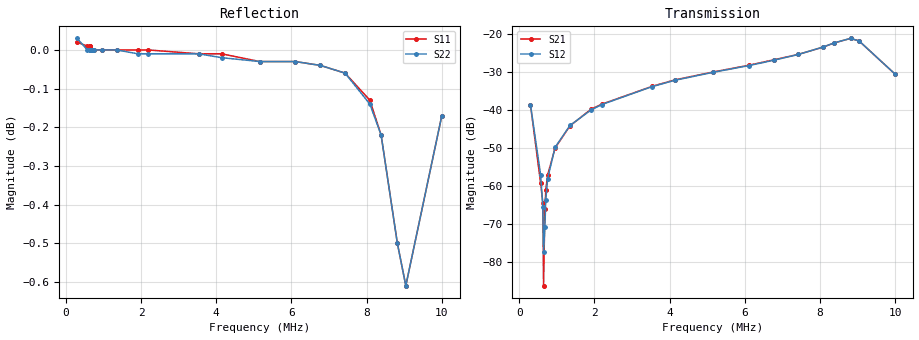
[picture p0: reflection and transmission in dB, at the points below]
!s-Parameter Generated by FASTRON Sdn. Bhd.
!FASTRON P/N : 1812AFTC-742X
!Keysight Technologies: E5071C_MY46733604_B.14.02
!Date: Wed Mar 18 14:06:43 2026
!Version  :Rev00  Wed Mar 18 14:06:43 2026
!Data & Calibration Information:
!Freq  S11:SOLT2(ON)  S21:SOLT2(ON)  S12:SOLT2(ON)  S22:SOLT2(ON)
!PortZ  Port1:50+j0  Port2:50+j0
!When reading reference impedance value at option line is always used.
! Remarks : This data is being provided solely for informational purposes.
# Hz S dB R 50
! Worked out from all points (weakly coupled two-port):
!   1601 points, 300 kHz to 10 MHz, reference 50 ohm
!   highest |S21| = -21.12 dB at 8.817 MHz (marker M1); lowest = -86.2 dB at 648.2 kHz (marker M2)
!   lowest |S11| = -0.6 dB at 9.042 MHz (marker M3), VSWR 28.63, Z = 7.12 - j87.5 ohm
!   |S11| at or under -10 dB: nowhere
!   |S22| runs from -0.6 to 0.0 dB; largest |S21 - S12| = 0.00093
!   S11 on the Smith chart (normalised r, x): 300 kHz: -0, +11; 2.195 MHz: 0.00, +1.35; 4.144 MHz: 0.00, +0.39; 6.102 MHz: 0.00, -0.20; 8.085 MHz: 0.01, -0.96; 10 MHz: 0.20, -4.36
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300000  0.02 10.4  -38.62 -84.4  -38.59 -86.0  0.03 -10.7
570598  0.01 19.0  -59.23 -75.7  -57.05 -78.5  0.00 -21.1
629177  0.01 20.9  -64.49 -49.6  -65.38 -64.0  0.00 -23.3
648216  0.01 21.6  -86.21 115.6  -77.33 -144.4  0.00 -24.0
683363  0.00 22.7  -66.06 112.3  -70.76 86.8  0.00 -25.3
708260  0.00 23.5  -61.01 72.7  -63.57 75.3  -0.00 -26.2
756588  0.00 25.2  -57.08 80.8  -58.02 82.5  0.00 -28.0
954971  0.00 31.7  -49.97 86.5  -49.80 88.2  -0.00 -35.3
1351274  0.00 44.9  -44.15 86.2  -44.03 84.1  -0.00 -50.0
1917564  -0.00 63.7  -39.72 84.4  -39.92 84.9  -0.01 -71.0
2195107  -0.00 72.9  -38.45 84.1  -38.55 84.6  -0.01 -81.2
3534704  -0.01 117.4  -33.75 80.8  -33.82 81.6  -0.01 -130.8
4143721  -0.01 137.6  -32.04 79.8  -32.15 79.7  -0.02 -153.4
5155786  -0.03 171.2  -29.98 75.3  -30.06 75.4  -0.03 169.1
6101602  -0.03 -157.5  -28.21 75.3  -28.30 75.2  -0.03 134.0
6770355  -0.04 -135.5  -26.77 73.0  -26.88 73.2  -0.04 109.1
7427816  -0.06 -113.9  -25.33 69.5  -25.35 69.8  -0.06 84.5
8084943  -0.13 -92.5  -23.43 62.5  -23.39 62.5  -0.14 59.6
8385344  -0.22 -82.9  -22.32 55.6  -22.29 55.6  -0.22 48.2
8817171  -0.50 -68.2  -21.12 34.9  -21.12 34.8  -0.50 32.6
9042472  -0.61 -59.3  -21.82 18.0  -21.80 18.0  -0.61 25.7
1e7  -0.17 -25.8  -30.54 32.2  -30.53 32.3  -0.17 -8.1
